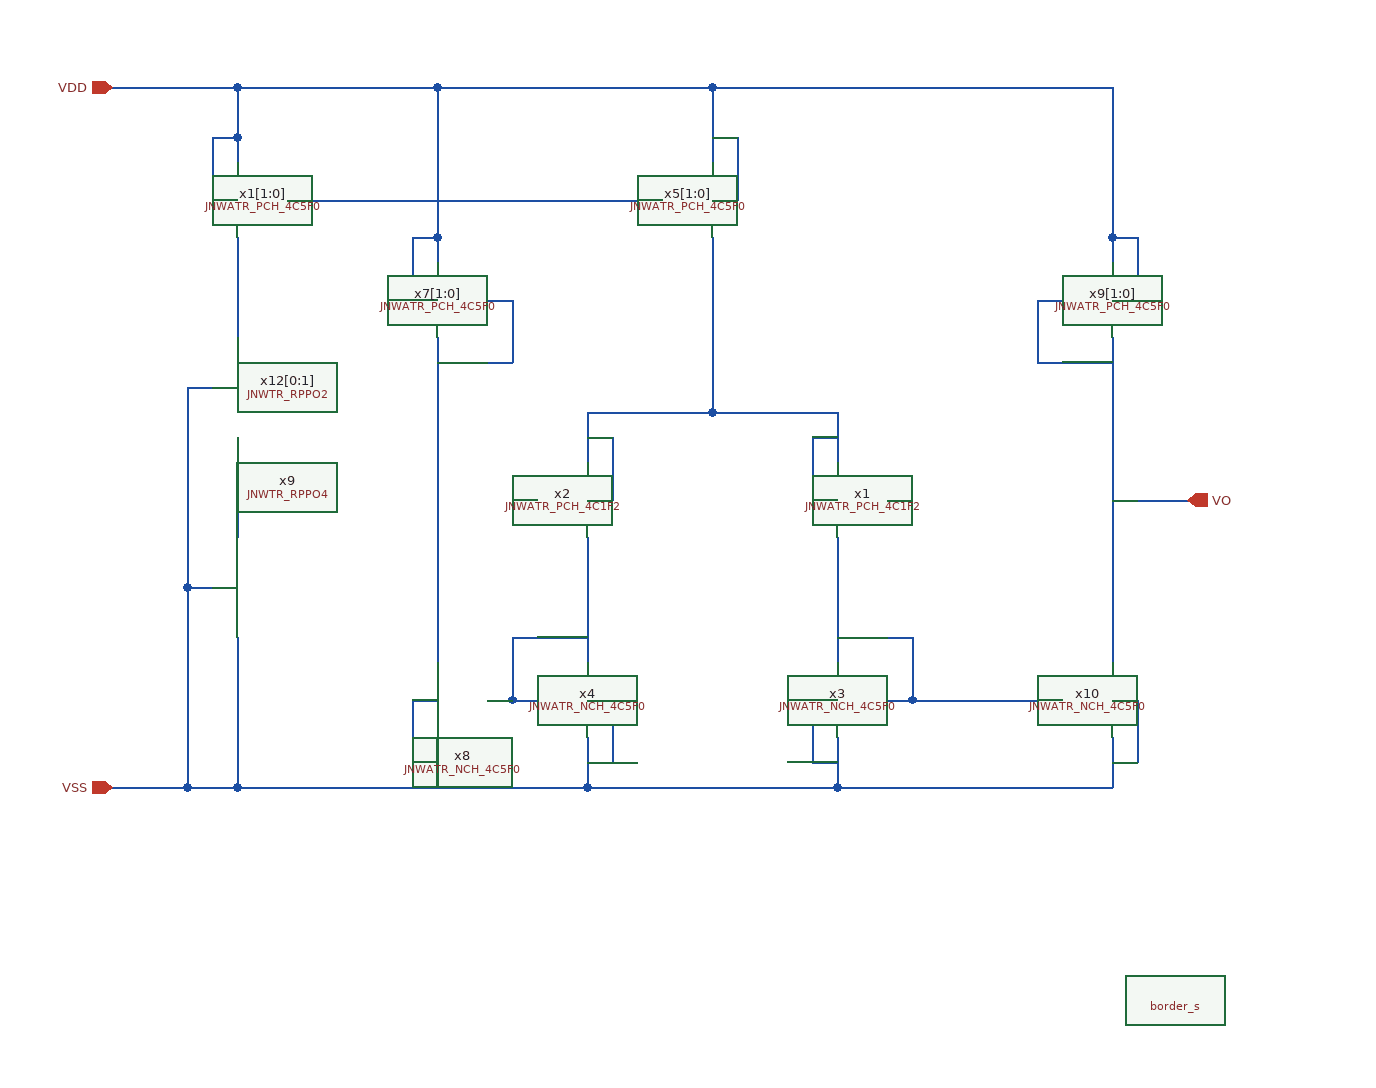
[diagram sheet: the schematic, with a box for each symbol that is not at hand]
v {xschem version=3.4.6 file_version=1.2}
G {}
K {type=subcircuit
format="@name @pinlist @symname"
template="name=x1"
}
V {}
S {}
E {}
N 1640 400 1640 460 {lab=#net1}
N 1540 460 1640 460 {lab=#net1}
N 1540 460 1540 500 {lab=#net1}
N 1640 460 1740 460 {lab=#net1}
N 1740 460 1740 500 {lab=#net1}
N 1540 530 1560 530 {lab=#net1}
N 1560 480 1560 530 {lab=#net1}
N 1540 480 1560 480 {lab=#net1}
N 1720 530 1740 530 {lab=#net1}
N 1720 480 1720 530 {lab=#net1}
N 1720 480 1740 480 {lab=#net1}
N 1540 560 1540 660 {lab=#net2}
N 1740 560 1740 660 {lab=#net3}
N 1480 530 1500 530 {lab=VIN}
N 1780 530 1800 530 {lab=VIP}
N 1420 400 1420 660 {lab=#net4}
N 1460 370 1480 370 {lab=#net4}
N 1480 370 1480 420 {lab=#net4}
N 1420 420 1480 420 {lab=#net4}
N 1400 370 1420 370 {lab=VDD}
N 1400 320 1400 370 {lab=VDD}
N 1400 320 1420 320 {lab=VDD}
N 1420 320 1420 340 {lab=VDD}
N 1420 280 1420 320 {lab=VDD}
N 1960 400 1960 660 {lab=#net5}
N 1900 370 1920 370 {lab=#net5}
N 1900 370 1900 420 {lab=#net5}
N 1900 420 1960 420 {lab=#net5}
N 1960 370 1980 370 {lab=VDD}
N 1980 320 1980 370 {lab=VDD}
N 1960 320 1980 320 {lab=VDD}
N 1960 320 1960 340 {lab=VDD}
N 1960 280 1960 320 {lab=VDD}
N 1740 640 1800 640 {lab=#net3}
N 1480 640 1540 640 {lab=#net2}
N 1480 640 1480 690 {lab=#net2}
N 1420 200 1420 280 {lab=VDD}
N 1960 200 1960 280 {lab=VDD}
N 1640 200 1960 200 {lab=VDD}
N 1420 200 1640 200 {lab=VDD}
N 1960 530 2020 530 {lab=#net5}
N 1420 720 1420 760 {lab=VSS}
N 1260 760 1540 760 {lab=VSS}
N 1540 760 1740 760 {lab=VSS}
N 1740 760 1960 760 {lab=VSS}
N 1960 720 1960 760 {lab=VSS}
N 1740 720 1740 760 {lab=VSS}
N 1540 720 1540 760 {lab=VSS}
N 1540 690 1560 690 {lab=VSS}
N 1560 690 1560 740 {lab=VSS}
N 1540 740 1560 740 {lab=VSS}
N 1400 690 1420 690 {lab=VSS}
N 1400 690 1400 740 {lab=VSS}
N 1400 740 1420 740 {lab=VSS}
N 1720 690 1740 690 {lab=VSS}
N 1720 690 1720 740 {lab=VSS}
N 1720 740 1740 740 {lab=VSS}
N 1960 690 1980 690 {lab=VSS}
N 1980 690 1980 740 {lab=VSS}
N 1960 740 1980 740 {lab=VSS}
N 1640 320 1640 400 {lab=#net1}
N 1640 200 1640 260 {lab=VDD}
N 1460 690 1480 690 {lab=#net2}
N 1480 690 1500 690 {lab=#net2}
N 1300 290 1600 290 {lab=#net6}
N 1640 290 1660 290 {lab=VDD}
N 1660 240 1660 290 {lab=VDD}
N 1640 240 1660 240 {lab=VDD}
N 1240 290 1260 290 {lab=VDD}
N 1240 240 1240 290 {lab=VDD}
N 1240 240 1260 240 {lab=VDD}
N 1260 240 1260 260 {lab=VDD}
N 1260 200 1260 240 {lab=VDD}
N 1260 200 1420 200 {lab=VDD}
N 1220 600 1240 600 {lab=VSS}
N 1220 600 1220 760 {lab=VSS}
N 1220 760 1260 760 {lab=VSS}
N 1260 640 1260 760 {lab=VSS}
N 1260 480 1260 560 {lab=#net7}
N 1220 440 1240 440 {lab=VSS}
N 1220 440 1220 600 {lab=VSS}
N 1260 320 1260 400 {lab=#net8}
N 1780 690 1800 690 {lab=#net3}
N 1800 640 1800 690 {lab=#net3}
N 1160 760 1220 760 {lab=VSS}
N 1160 200 1260 200 {lab=VDD}
N 1800 690 1920 690 {lab=#net3}
C {cborder/border_s.sym} 2010 930 0 0 {
user="wulff"
company="wulff"}
C {devices/ipin.sym} 1480 530 2 1 {name=VIN lab=VIN}
C {devices/ipin.sym} 1800 530 2 0 {name=VIP lab=VIP}
C {devices/ipin.sym} 1160 760 0 0 {name=VSS lab=VSS}
C {devices/ipin.sym} 1160 200 0 0 {name=VDD lab=VDD}
C {JNW_ATR_SKY130A/JNWATR_PCH_4C1F2.sym} 1500 530 0 0 {name=x2}
C {JNW_ATR_SKY130A/JNWATR_PCH_4C1F2.sym} 1780 530 0 1 {name=x1}
C {JNW_ATR_SKY130A/JNWATR_NCH_4C5F0.sym} 1780 690 0 1 {name=x3}
C {JNW_ATR_SKY130A/JNWATR_NCH_4C5F0.sym} 1500 690 0 0 {name=x4}
C {JNW_ATR_SKY130A/JNWATR_NCH_4C5F0.sym} 1920 690 0 0 {name=x10}
C {JNW_ATR_SKY130A/JNWATR_NCH_4C5F0.sym} 1460 690 0 1 {name=x8}
C {JNW_ATR_SKY130A/JNWATR_PCH_4C5F0.sym} 1460 370 0 1 {name=x7[1:0]}
C {JNW_ATR_SKY130A/JNWATR_PCH_4C5F0.sym} 1920 370 0 0 {name=x9[1:0]}
C {JNW_ATR_SKY130A/JNWATR_PCH_4C5F0.sym} 1300 290 0 1 {name=x1[1:0]}
C {JNW_ATR_SKY130A/JNWATR_PCH_4C5F0.sym} 1600 290 0 0 {name=x5[1:0]}
C {JNW_TR_SKY130A/JNWTR_RPPO4.sym} 1260 560 1 0 {name=x9 }
C {JNW_TR_SKY130A/JNWTR_RPPO2.sym} 1260 400 1 0 {name=x12[0:1]}
C {devices/ipin.sym} 2020 530 0 1 {name=VO lab=VO}
